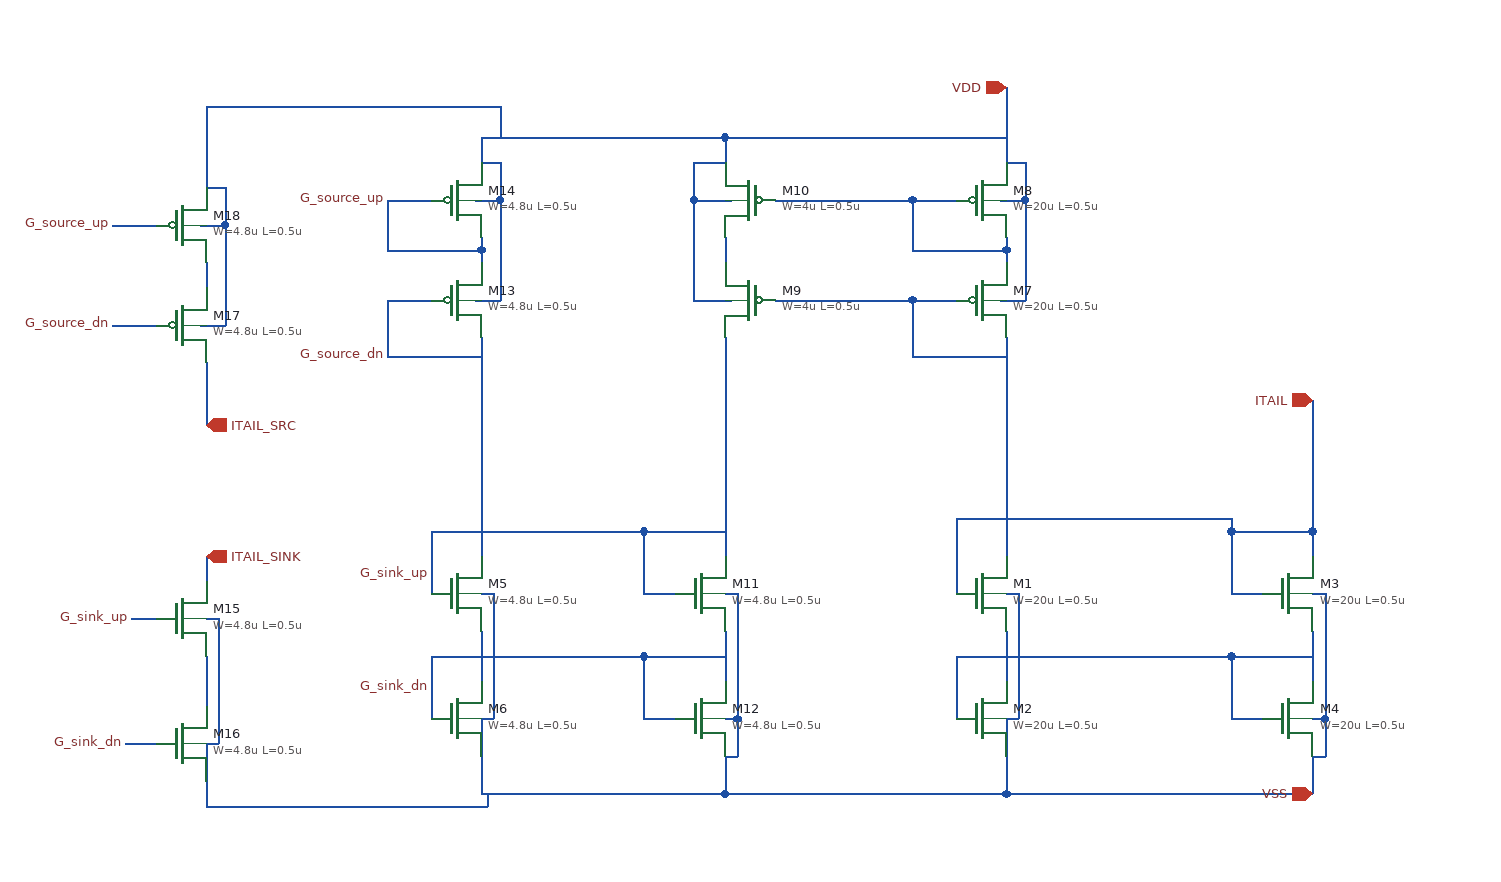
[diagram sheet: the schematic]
v {xschem version=3.1.0 file_version=1.2
}
G {}
K {}
V {}
S {}
E {}
N 835 -315 845 -315 {
lab=VSS}
N 845 -315 845 -215 {
lab=VSS}
N 835 -215 845 -215 {
lab=VSS}
N 835 -280 835 -250 {
lab=#net1}
N 835 -285 835 -280 {
lab=#net1}
N 835 -250 835 -245 {
lab=#net1}
N 835 -215 835 -160 {
lab=VSS}
N 835 -355 835 -345 {
lab=#net2}
N 835 -160 835 -155 {
lab=VSS}
N 835 -520 835 -355 {
lab=#net2}
N 760 -630 795 -630 {
lab=#net3}
N 760 -630 760 -590 {
lab=#net3}
N 760 -590 835 -590 {
lab=#net3}
N 835 -600 835 -590 {
lab=#net3}
N 835 -590 835 -580 {
lab=#net3}
N 830 -550 850 -550 {
lab=VDD}
N 850 -630 850 -550 {
lab=VDD}
N 830 -630 850 -630 {
lab=VDD}
N 850 -660 850 -630 {
lab=VDD}
N 835 -660 850 -660 {
lab=VDD}
N 835 -720 835 -660 {
lab=VDD}
N 760 -550 795 -550 {
lab=#net2}
N 760 -550 760 -505 {
lab=#net2}
N 760 -505 835 -505 {
lab=#net2}
N 650 -630 760 -630 {
lab=#net3}
N 650 -550 760 -550 {
lab=#net2}
N 610 -600 610 -580 {
lab=#net4}
N 610 -680 610 -660 {
lab=VDD}
N 610 -680 835 -680 {
lab=VDD}
N 610 -520 610 -445 {
lab=G_sink_up}
N 585 -550 615 -550 {
lab=VDD}
N 585 -630 585 -550 {
lab=VDD}
N 585 -630 615 -630 {
lab=VDD}
N 585 -630 615 -630 {
lab=VDD}
N 585 -660 585 -630 {
lab=VDD}
N 585 -660 610 -660 {
lab=VDD}
N 610 -445 610 -345 {
lab=G_sink_up}
N 610 -285 610 -245 {
lab=#net5}
N 610 -315 620 -315 {
lab=VSS}
N 620 -315 620 -215 {
lab=VSS}
N 610 -215 620 -215 {
lab=VSS}
N 610 -215 620 -215 {
lab=VSS}
N 620 -215 620 -185 {
lab=VSS}
N 610 -185 620 -185 {
lab=VSS}
N 610 -185 610 -155 {
lab=VSS}
N 610 -155 835 -155 {
lab=VSS}
N 545 -315 570 -315 {
lab=G_sink_up}
N 545 -365 545 -315 {
lab=G_sink_up}
N 545 -265 610 -265 {
lab=#net5}
N 545 -265 545 -215 {
lab=#net5}
N 545 -215 570 -215 {
lab=#net5}
N 545 -365 610 -365 {
lab=G_sink_up}
N 795 -375 795 -315 {
lab=ITAIL}
N 795 -375 1015 -375 {
lab=ITAIL}
N 795 -265 795 -215 {
lab=#net6}
N 795 -265 1010 -265 {
lab=#net6}
N 1080 -285 1080 -245 {
lab=#net6}
N 1080 -315 1090 -315 {
lab=VSS}
N 1090 -315 1090 -215 {
lab=VSS}
N 1080 -215 1090 -215 {
lab=VSS}
N 1080 -215 1090 -215 {
lab=VSS}
N 1090 -215 1090 -185 {
lab=VSS}
N 1080 -185 1090 -185 {
lab=VSS}
N 1080 -185 1080 -155 {
lab=VSS}
N 1015 -315 1040 -315 {
lab=ITAIL}
N 1015 -365 1015 -315 {
lab=ITAIL}
N 1015 -265 1080 -265 {
lab=#net6}
N 1015 -265 1015 -215 {
lab=#net6}
N 1015 -215 1040 -215 {
lab=#net6}
N 1015 -365 1080 -365 {
lab=ITAIL}
N 1010 -265 1015 -265 {
lab=#net6}
N 1015 -375 1015 -365 {
lab=ITAIL}
N 1080 -365 1080 -345 {
lab=ITAIL}
N 835 -155 1080 -155 {
lab=VSS}
N 1080 -470 1080 -365 {
lab=ITAIL}
N 415 -315 425 -315 {
lab=VSS}
N 425 -315 425 -215 {
lab=VSS}
N 415 -215 425 -215 {
lab=VSS}
N 415 -280 415 -250 {
lab=#net7}
N 415 -285 415 -280 {
lab=#net7}
N 415 -250 415 -245 {
lab=#net7}
N 415 -355 415 -345 {
lab=G_source_dn}
N 415 -520 415 -355 {
lab=G_source_dn}
N 340 -630 375 -630 {
lab=G_source_up}
N 340 -630 340 -590 {
lab=G_source_up}
N 340 -590 415 -590 {
lab=G_source_up}
N 415 -600 415 -590 {
lab=G_source_up}
N 415 -590 415 -580 {
lab=G_source_up}
N 410 -550 430 -550 {
lab=VDD}
N 430 -630 430 -550 {
lab=VDD}
N 410 -630 430 -630 {
lab=VDD}
N 430 -660 430 -630 {
lab=VDD}
N 415 -660 430 -660 {
lab=VDD}
N 340 -550 375 -550 {
lab=G_source_dn}
N 340 -550 340 -505 {
lab=G_source_dn}
N 340 -505 415 -505 {
lab=G_source_dn}
N 375 -265 375 -215 {
lab=#net5}
N 415 -185 415 -155 {
lab=VSS}
N 415 -155 610 -155 {
lab=VSS}
N 415 -215 415 -185 {
lab=VSS}
N 415 -680 610 -680 {
lab=VDD}
N 415 -680 415 -660 {
lab=VDD}
N 375 -365 545 -365 {
lab=G_sink_up}
N 375 -365 375 -315 {
lab=G_sink_up}
N 375 -265 545 -265 {
lab=#net5}
N 195 -295 205 -295 {
lab=VSS}
N 205 -295 205 -195 {
lab=VSS}
N 195 -195 205 -195 {
lab=VSS}
N 195 -260 195 -230 {
lab=#net8}
N 195 -265 195 -260 {
lab=#net8}
N 195 -230 195 -225 {
lab=#net8}
N 195 -335 195 -325 {
lab=ITAIL_SINK}
N 120 -610 155 -610 {
lab=G_source_up}
N 195 -580 195 -570 {
lab=#net9}
N 195 -570 195 -560 {
lab=#net9}
N 190 -530 210 -530 {
lab=VDD}
N 210 -610 210 -530 {
lab=VDD}
N 190 -610 210 -610 {
lab=VDD}
N 210 -640 210 -610 {
lab=VDD}
N 195 -640 210 -640 {
lab=VDD}
N 120 -530 155 -530 {
lab=G_source_dn}
N 195 -195 195 -165 {
lab=VSS}
N 195 -660 195 -640 {
lab=VDD}
N 195 -345 195 -335 {
lab=ITAIL_SINK}
N 130 -195 155 -195 {
lab=G_sink_dn}
N 195 -705 195 -660 {
lab=VDD}
N 195 -705 430 -705 {
lab=VDD}
N 430 -705 430 -680 {
lab=VDD}
N 195 -165 195 -145 {
lab=VSS}
N 195 -145 420 -145 {
lab=VSS}
N 420 -155 420 -145 {
lab=VSS}
N 135 -295 155 -295 {
lab=G_sink_up}
N 195 -500 195 -450 {
lab=ITAIL_SRC}
C {symbols/nfet_03v3.sym} 815 -315 0 0 {name=M1
L=0.5u
W=20u
nf=1
m=1
ad="'int((nf+1)/2) * W/nf * 0.18u'"
pd="'2*int((nf+1)/2) * (W/nf + 0.18u)'"
as="'int((nf+2)/2) * W/nf * 0.18u'"
ps="'2*int((nf+2)/2) * (W/nf + 0.18u)'"
nrd="'0.18u / W'" nrs="'0.18u / W'"
sa=0 sb=0 sd=0
model=nfet_03v3
spiceprefix=X
}
C {symbols/nfet_03v3.sym} 815 -215 0 0 {name=M2
L=0.5u
W=20u
nf=1
m=1
ad="'int((nf+1)/2) * W/nf * 0.18u'"
pd="'2*int((nf+1)/2) * (W/nf + 0.18u)'"
as="'int((nf+2)/2) * W/nf * 0.18u'"
ps="'2*int((nf+2)/2) * (W/nf + 0.18u)'"
nrd="'0.18u / W'" nrs="'0.18u / W'"
sa=0 sb=0 sd=0
model=nfet_03v3
spiceprefix=X
}
C {symbols/pfet_03v3.sym} 815 -550 0 0 {name=M7
L=0.5u
W=20u
nf=1
m=1
ad="'int((nf+1)/2) * W/nf * 0.18u'"
pd="'2*int((nf+1)/2) * (W/nf + 0.18u)'"
as="'int((nf+2)/2) * W/nf * 0.18u'"
ps="'2*int((nf+2)/2) * (W/nf + 0.18u)'"
nrd="'0.18u / W'" nrs="'0.18u / W'"
sa=0 sb=0 sd=0
model=pfet_03v3
spiceprefix=X
}
C {symbols/pfet_03v3.sym} 815 -630 0 0 {name=M8
L=0.5u
W=20u
nf=1
m=1
ad="'int((nf+1)/2) * W/nf * 0.18u'"
pd="'2*int((nf+1)/2) * (W/nf + 0.18u)'"
as="'int((nf+2)/2) * W/nf * 0.18u'"
ps="'2*int((nf+2)/2) * (W/nf + 0.18u)'"
nrd="'0.18u / W'" nrs="'0.18u / W'"
sa=0 sb=0 sd=0
model=pfet_03v3
spiceprefix=X
}
C {symbols/pfet_03v3.sym} 630 -550 0 1 {name=M9
L=0.5u
W=4u
nf=1
m=1
ad="'int((nf+1)/2) * W/nf * 0.18u'"
pd="'2*int((nf+1)/2) * (W/nf + 0.18u)'"
as="'int((nf+2)/2) * W/nf * 0.18u'"
ps="'2*int((nf+2)/2) * (W/nf + 0.18u)'"
nrd="'0.18u / W'" nrs="'0.18u / W'"
sa=0 sb=0 sd=0
model=pfet_03v3
spiceprefix=X
}
C {symbols/pfet_03v3.sym} 630 -630 0 1 {name=M10
L=0.5u
W=4u
nf=1
m=1
ad="'int((nf+1)/2) * W/nf * 0.18u'"
pd="'2*int((nf+1)/2) * (W/nf + 0.18u)'"
as="'int((nf+2)/2) * W/nf * 0.18u'"
ps="'2*int((nf+2)/2) * (W/nf + 0.18u)'"
nrd="'0.18u / W'" nrs="'0.18u / W'"
sa=0 sb=0 sd=0
model=pfet_03v3
spiceprefix=X
}
C {symbols/nfet_03v3.sym} 590 -315 0 0 {name=M11
L=0.5u
W=4.8u
nf=1
m=1
ad="'int((nf+1)/2) * W/nf * 0.18u'"
pd="'2*int((nf+1)/2) * (W/nf + 0.18u)'"
as="'int((nf+2)/2) * W/nf * 0.18u'"
ps="'2*int((nf+2)/2) * (W/nf + 0.18u)'"
nrd="'0.18u / W'" nrs="'0.18u / W'"
sa=0 sb=0 sd=0
model=nfet_03v3
spiceprefix=X
}
C {symbols/nfet_03v3.sym} 590 -215 0 0 {name=M12
L=0.5u
W=4.8u
nf=1
m=1
ad="'int((nf+1)/2) * W/nf * 0.18u'"
pd="'2*int((nf+1)/2) * (W/nf + 0.18u)'"
as="'int((nf+2)/2) * W/nf * 0.18u'"
ps="'2*int((nf+2)/2) * (W/nf + 0.18u)'"
nrd="'0.18u / W'" nrs="'0.18u / W'"
sa=0 sb=0 sd=0
model=nfet_03v3
spiceprefix=X
}
C {devices/ipin.sym} 1080 -470 0 0 {name=p8 lab=ITAIL}
C {devices/iopin.sym} 835 -720 0 0 {name=p9 lab=VDD}
C {devices/iopin.sym} 1080 -155 0 0 {name=p10 lab=VSS}
C {symbols/nfet_03v3.sym} 1060 -315 0 0 {name=M3
L=0.5u
W=20u
nf=1
m=1
ad="'int((nf+1)/2) * W/nf * 0.18u'"
pd="'2*int((nf+1)/2) * (W/nf + 0.18u)'"
as="'int((nf+2)/2) * W/nf * 0.18u'"
ps="'2*int((nf+2)/2) * (W/nf + 0.18u)'"
nrd="'0.18u / W'" nrs="'0.18u / W'"
sa=0 sb=0 sd=0
model=nfet_03v3
spiceprefix=X
}
C {symbols/nfet_03v3.sym} 1060 -215 0 0 {name=M4
L=0.5u
W=20u
nf=1
m=1
ad="'int((nf+1)/2) * W/nf * 0.18u'"
pd="'2*int((nf+1)/2) * (W/nf + 0.18u)'"
as="'int((nf+2)/2) * W/nf * 0.18u'"
ps="'2*int((nf+2)/2) * (W/nf + 0.18u)'"
nrd="'0.18u / W'" nrs="'0.18u / W'"
sa=0 sb=0 sd=0
model=nfet_03v3
spiceprefix=X
}
C {symbols/nfet_03v3.sym} 395 -315 0 0 {name=M5
L=0.5u
W=4.8u
nf=1
m=1
ad="'int((nf+1)/2) * W/nf * 0.18u'"
pd="'2*int((nf+1)/2) * (W/nf + 0.18u)'"
as="'int((nf+2)/2) * W/nf * 0.18u'"
ps="'2*int((nf+2)/2) * (W/nf + 0.18u)'"
nrd="'0.18u / W'" nrs="'0.18u / W'"
sa=0 sb=0 sd=0
model=nfet_03v3
spiceprefix=X
}
C {symbols/nfet_03v3.sym} 395 -215 0 0 {name=M6
L=0.5u
W=4.8u
nf=1
m=1
ad="'int((nf+1)/2) * W/nf * 0.18u'"
pd="'2*int((nf+1)/2) * (W/nf + 0.18u)'"
as="'int((nf+2)/2) * W/nf * 0.18u'"
ps="'2*int((nf+2)/2) * (W/nf + 0.18u)'"
nrd="'0.18u / W'" nrs="'0.18u / W'"
sa=0 sb=0 sd=0
model=nfet_03v3
spiceprefix=X
}
C {symbols/pfet_03v3.sym} 395 -550 0 0 {name=M13
L=0.5u
W=4.8u
nf=1
m=1
ad="'int((nf+1)/2) * W/nf * 0.18u'"
pd="'2*int((nf+1)/2) * (W/nf + 0.18u)'"
as="'int((nf+2)/2) * W/nf * 0.18u'"
ps="'2*int((nf+2)/2) * (W/nf + 0.18u)'"
nrd="'0.18u / W'" nrs="'0.18u / W'"
sa=0 sb=0 sd=0
model=pfet_03v3
spiceprefix=X
}
C {symbols/pfet_03v3.sym} 395 -630 0 0 {name=M14
L=0.5u
W=4.8u
nf=1
m=1
ad="'int((nf+1)/2) * W/nf * 0.18u'"
pd="'2*int((nf+1)/2) * (W/nf + 0.18u)'"
as="'int((nf+2)/2) * W/nf * 0.18u'"
ps="'2*int((nf+2)/2) * (W/nf + 0.18u)'"
nrd="'0.18u / W'" nrs="'0.18u / W'"
sa=0 sb=0 sd=0
model=pfet_03v3
spiceprefix=X
}
C {symbols/nfet_03v3.sym} 175 -295 0 0 {name=M15
L=0.5u
W=4.8u
nf=1
m=1
ad="'int((nf+1)/2) * W/nf * 0.18u'"
pd="'2*int((nf+1)/2) * (W/nf + 0.18u)'"
as="'int((nf+2)/2) * W/nf * 0.18u'"
ps="'2*int((nf+2)/2) * (W/nf + 0.18u)'"
nrd="'0.18u / W'" nrs="'0.18u / W'"
sa=0 sb=0 sd=0
model=nfet_03v3
spiceprefix=X
}
C {symbols/nfet_03v3.sym} 175 -195 0 0 {name=M16
L=0.5u
W=4.8u
nf=1
m=1
ad="'int((nf+1)/2) * W/nf * 0.18u'"
pd="'2*int((nf+1)/2) * (W/nf + 0.18u)'"
as="'int((nf+2)/2) * W/nf * 0.18u'"
ps="'2*int((nf+2)/2) * (W/nf + 0.18u)'"
nrd="'0.18u / W'" nrs="'0.18u / W'"
sa=0 sb=0 sd=0
model=nfet_03v3
spiceprefix=X
}
C {symbols/pfet_03v3.sym} 175 -530 0 0 {name=M17
L=0.5u
W=4.8u
nf=1
m=1
ad="'int((nf+1)/2) * W/nf * 0.18u'"
pd="'2*int((nf+1)/2) * (W/nf + 0.18u)'"
as="'int((nf+2)/2) * W/nf * 0.18u'"
ps="'2*int((nf+2)/2) * (W/nf + 0.18u)'"
nrd="'0.18u / W'" nrs="'0.18u / W'"
sa=0 sb=0 sd=0
model=pfet_03v3
spiceprefix=X
}
C {symbols/pfet_03v3.sym} 175 -610 0 0 {name=M18
L=0.5u
W=4.8u
nf=1
m=1
ad="'int((nf+1)/2) * W/nf * 0.18u'"
pd="'2*int((nf+1)/2) * (W/nf + 0.18u)'"
as="'int((nf+2)/2) * W/nf * 0.18u'"
ps="'2*int((nf+2)/2) * (W/nf + 0.18u)'"
nrd="'0.18u / W'" nrs="'0.18u / W'"
sa=0 sb=0 sd=0
model=pfet_03v3
spiceprefix=X
}
C {devices/lab_pin.sym} 120 -610 0 0 {name=p1 sig_type=std_logic lab=G_source_up}
C {devices/lab_pin.sym} 120 -530 0 0 {name=p2 sig_type=std_logic lab=G_source_dn}
C {devices/lab_pin.sym} 135 -295 0 0 {name=p6 sig_type=std_logic lab=G_sink_up}
C {devices/lab_pin.sym} 130 -195 0 0 {name=p7 sig_type=std_logic lab=G_sink_dn}
C {devices/opin.sym} 195 -450 0 0 {name=p11 lab=ITAIL_SRC}
C {devices/opin.sym} 195 -345 0 0 {name=p12 lab=ITAIL_SINK}
C {devices/lab_pin.sym} 340 -630 0 0 {name=p3 sig_type=std_logic lab=G_source_up}
C {devices/lab_pin.sym} 340 -505 0 0 {name=p4 sig_type=std_logic lab=G_source_dn}
C {devices/lab_pin.sym} 375 -330 0 0 {name=p5 sig_type=std_logic lab=G_sink_up}
C {devices/lab_pin.sym} 375 -240 0 0 {name=p13 sig_type=std_logic lab=G_sink_dn}
